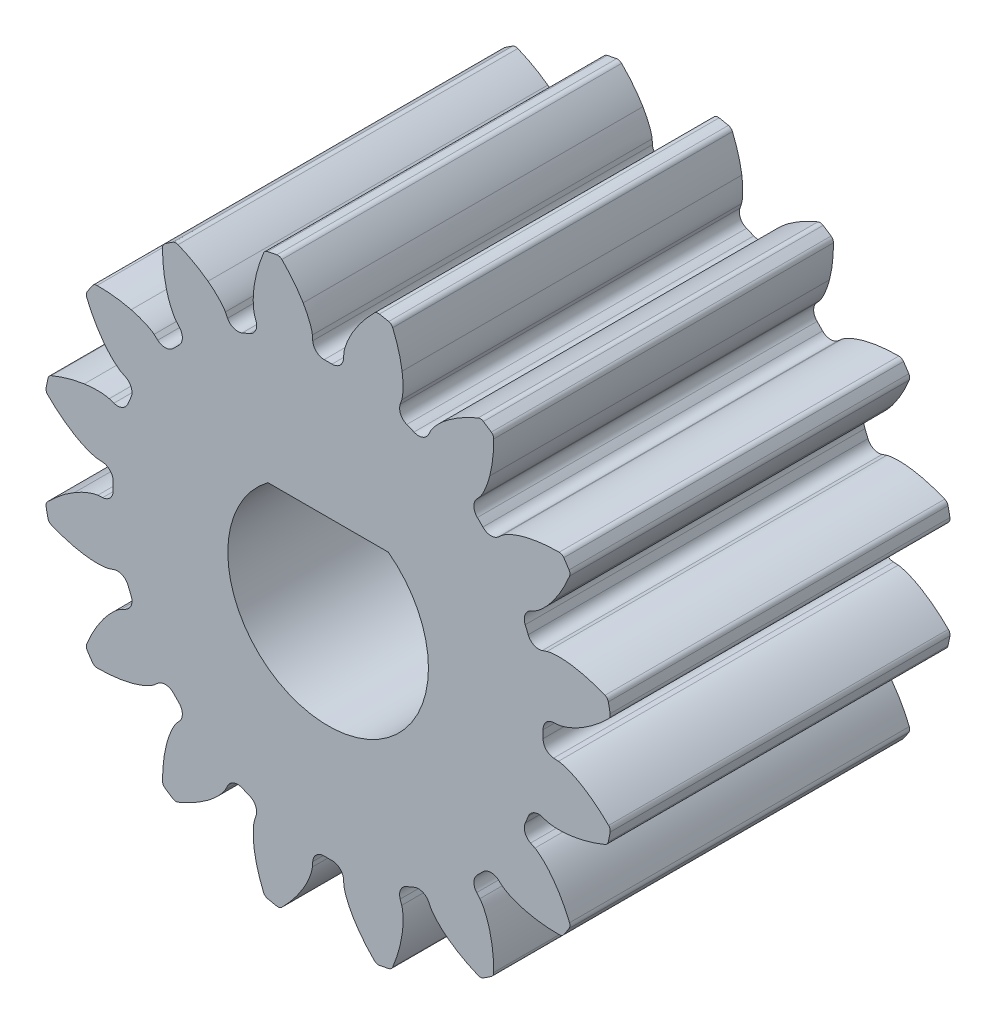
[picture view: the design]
SolidWorks part; units mm, degrees
ref_plane "Front Plane" through (0, 0, 0) normal (0, 0, 1) x (1, 0, 0)
ref_plane "Top Plane" through (0, 0, 0) normal (0, 1, 0) x (1, 0, 0)
ref_plane "Right Plane" through (0, 0, 0) normal (1, 0, 0) x (0, 0, -1)
sketch "Sketch1" plane through (0, 0, 0) normal (0, 0, 1) x (1, 0, 0)
  line L1 (-1.8, 2.4) -> (1.8, 2.4)
  circle A0 centre (0, 0) radius 7.62
  arc A2 (-1.8, 2.4) -> (1.8, 2.4) centre (0, 0) ccw
  dimension "D1" = 15.24
extrude "Boss-Extrude1" add sketch "Sketch1" against normal blind 10.16
sketch "Sketch2" plane through (0, 0, 0) normal (0, 0, 1) x (1, 0, 0)
  line L0 (3.0715, 6.1854) -> (3.0064, 6.0543)
  line L1 (2.1552, 6.4069) -> (2.2019, 6.5456)
  line L2 (0.4706, 6.89) -> (0.4606, 6.7439)
  line L3 (-0.4606, 6.7439) -> (-0.4706, 6.89)
  line L4 (-2.2019, 6.5456) -> (-2.1552, 6.4069)
  line L5 (-3.0064, 6.0543) -> (-3.0715, 6.1854)
  line L6 (-4.5392, 5.2048) -> (-4.443, 5.0944)
  line L7 (-5.0944, 4.443) -> (-5.2048, 4.5392)
  line L8 (-6.1854, 3.0715) -> (-6.0543, 3.0064)
  line L9 (-6.4069, 2.1552) -> (-6.5456, 2.2019)
  line L10 (-6.89, 0.4706) -> (-6.7439, 0.4606)
  line L11 (-6.7439, -0.4606) -> (-6.89, -0.4706)
  line L12 (-6.5456, -2.2019) -> (-6.4069, -2.1552)
  line L13 (-6.0543, -3.0064) -> (-6.1854, -3.0715)
  line L14 (-5.2048, -4.5392) -> (-5.0944, -4.443)
  line L15 (-4.443, -5.0944) -> (-4.5392, -5.2048)
  line L16 (-3.0715, -6.1854) -> (-3.0064, -6.0543)
  line L17 (-2.1552, -6.4069) -> (-2.2019, -6.5456)
  line L18 (-0.4706, -6.89) -> (-0.4606, -6.7439)
  line L19 (0.4606, -6.7439) -> (0.4706, -6.89)
  line L20 (2.2019, -6.5456) -> (2.1552, -6.4069)
  line L21 (3.0064, -6.0543) -> (3.0715, -6.1854)
  line L22 (4.5392, -5.2048) -> (4.443, -5.0944)
  line L23 (5.0944, -4.443) -> (5.2048, -4.5392)
  line L24 (6.1854, -3.0715) -> (6.0543, -3.0064)
  line L25 (6.4069, -2.1552) -> (6.5456, -2.2019)
  line L26 (6.89, -0.4706) -> (6.7439, -0.4606)
  line L27 (6.7439, 0.4606) -> (6.89, 0.4706)
  line L28 (6.5456, 2.2019) -> (6.4069, 2.1552)
  line L29 (6.0543, 3.0064) -> (6.1854, 3.0715)
  line L30 (5.2048, 4.5392) -> (5.0944, 4.443)
  line L31 (4.443, 5.0944) -> (4.5392, 5.2048)
  arc A2 (2.5677, 5.8944) -> (3.0064, 6.0543) centre (2.703, 6.205) ccw
  arc A3 (2.5677, 5.8944) -> (2.3523, 5.9836) centre (0, 0) ccw
  arc A4 (2.1552, 6.4069) -> (2.3523, 5.9836) centre (2.4763, 6.2989) ccw
  arc A8 (0.1165, 6.4283) -> (0.4606, 6.7439) centre (0.1227, 6.767) ccw
  arc A9 (0.1165, 6.4283) -> (-0.1165, 6.4283) centre (0, 0) ccw
  arc A10 (-0.4606, 6.7439) -> (-0.1165, 6.4283) centre (-0.1227, 6.767) ccw
  arc A14 (-2.3523, 5.9836) -> (-2.1552, 6.4069) centre (-2.4763, 6.2989) ccw
  arc A15 (-2.3523, 5.9836) -> (-2.5677, 5.8944) centre (0, 0) ccw
  arc A16 (-3.0064, 6.0543) -> (-2.5677, 5.8944) centre (-2.703, 6.205) ccw
  arc A20 (-4.4631, 4.6279) -> (-4.443, 5.0944) centre (-4.6983, 4.8718) ccw
  arc A21 (-4.4631, 4.6279) -> (-4.6279, 4.4631) centre (0, 0) ccw
  arc A22 (-5.0944, 4.443) -> (-4.6279, 4.4631) centre (-4.8718, 4.6983) ccw
  arc A26 (-5.8944, 2.5677) -> (-6.0543, 3.0064) centre (-6.205, 2.703) ccw
  arc A27 (-5.8944, 2.5677) -> (-5.9836, 2.3523) centre (0, 0) ccw
  arc A28 (-6.4069, 2.1552) -> (-5.9836, 2.3523) centre (-6.2989, 2.4763) ccw
  arc A32 (-6.4283, 0.1165) -> (-6.7439, 0.4606) centre (-6.767, 0.1227) ccw
  arc A33 (-6.4283, 0.1165) -> (-6.4283, -0.1165) centre (0, 0) ccw
  arc A34 (-6.7439, -0.4606) -> (-6.4283, -0.1165) centre (-6.767, -0.1227) ccw
  arc A38 (-5.9836, -2.3523) -> (-6.4069, -2.1552) centre (-6.2989, -2.4763) ccw
  arc A39 (-5.9836, -2.3523) -> (-5.8944, -2.5677) centre (0, 0) ccw
  arc A40 (-6.0543, -3.0064) -> (-5.8944, -2.5677) centre (-6.205, -2.703) ccw
  arc A44 (-4.6279, -4.4631) -> (-5.0944, -4.443) centre (-4.8718, -4.6983) ccw
  arc A45 (-4.6279, -4.4631) -> (-4.4631, -4.6279) centre (0, 0) ccw
  arc A46 (-4.443, -5.0944) -> (-4.4631, -4.6279) centre (-4.6983, -4.8718) ccw
  arc A50 (-2.5677, -5.8944) -> (-3.0064, -6.0543) centre (-2.703, -6.205) ccw
  arc A51 (-2.5677, -5.8944) -> (-2.3523, -5.9836) centre (0, 0) ccw
  arc A52 (-2.1552, -6.4069) -> (-2.3523, -5.9836) centre (-2.4763, -6.2989) ccw
  arc A56 (-0.1165, -6.4283) -> (-0.4606, -6.7439) centre (-0.1227, -6.767) ccw
  arc A57 (-0.1165, -6.4283) -> (0.1165, -6.4283) centre (0, 0) ccw
  arc A58 (0.4606, -6.7439) -> (0.1165, -6.4283) centre (0.1227, -6.767) ccw
  arc A62 (2.3523, -5.9836) -> (2.1552, -6.4069) centre (2.4763, -6.2989) ccw
  arc A63 (2.3523, -5.9836) -> (2.5677, -5.8944) centre (0, 0) ccw
  arc A64 (3.0064, -6.0543) -> (2.5677, -5.8944) centre (2.703, -6.205) ccw
  arc A68 (4.4631, -4.6279) -> (4.443, -5.0944) centre (4.6983, -4.8718) ccw
  arc A69 (4.4631, -4.6279) -> (4.6279, -4.4631) centre (0, 0) ccw
  arc A70 (5.0944, -4.443) -> (4.6279, -4.4631) centre (4.8718, -4.6983) ccw
  arc A74 (5.8944, -2.5677) -> (6.0543, -3.0064) centre (6.205, -2.703) ccw
  arc A75 (5.8944, -2.5677) -> (5.9836, -2.3523) centre (0, 0) ccw
  arc A76 (6.4069, -2.1552) -> (5.9836, -2.3523) centre (6.2989, -2.4763) ccw
  arc A80 (6.4283, -0.1165) -> (6.7439, -0.4606) centre (6.767, -0.1227) ccw
  arc A81 (6.4283, -0.1165) -> (6.4283, 0.1165) centre (0, 0) ccw
  arc A82 (6.7439, 0.4606) -> (6.4283, 0.1165) centre (6.767, 0.1227) ccw
  arc A86 (5.9836, 2.3523) -> (6.4069, 2.1552) centre (6.2989, 2.4763) ccw
  arc A87 (5.9836, 2.3523) -> (5.8944, 2.5677) centre (0, 0) ccw
  arc A88 (6.0543, 3.0064) -> (5.8944, 2.5677) centre (6.205, 2.703) ccw
  arc A92 (4.6279, 4.4631) -> (5.0944, 4.443) centre (4.8718, 4.6983) ccw
  arc A93 (4.6279, 4.4631) -> (4.4631, 4.6279) centre (0, 0) ccw
  arc A94 (4.443, 5.0944) -> (4.4631, 4.6279) centre (4.6983, 4.8718) ccw
  circle A96 centre (0, 0) radius 7.62 construction
  arc A97 (-2.212, 7.2919) -> (-3.592, 6.7202) centre (0, 0) ccw
  arc A98 (-4.8341, 5.8903) -> (-5.8903, 4.8341) centre (0, 0) ccw
  arc A99 (-6.7202, 3.592) -> (-7.2919, 2.212) centre (0, 0) ccw
  arc A100 (-7.5833, 0.7469) -> (-7.5833, -0.7469) centre (0, 0) ccw
  arc A101 (-7.2919, -2.212) -> (-6.7202, -3.592) centre (0, 0) ccw
  arc A102 (-5.8903, -4.8341) -> (-4.8341, -5.8903) centre (0, 0) ccw
  arc A103 (-3.592, -6.7202) -> (-2.212, -7.2919) centre (0, 0) ccw
  arc A104 (-0.7469, -7.5833) -> (0.7469, -7.5833) centre (0, 0) ccw
  arc A105 (2.212, -7.2919) -> (3.592, -6.7202) centre (0, 0) ccw
  arc A106 (4.8341, -5.8903) -> (5.8903, -4.8341) centre (0, 0) ccw
  arc A107 (6.7202, -3.592) -> (7.2919, -2.212) centre (0, 0) ccw
  arc A108 (7.5833, -0.7469) -> (7.5833, 0.7469) centre (0, 0) ccw
  arc A109 (7.2919, 2.212) -> (6.7202, 3.592) centre (0, 0) ccw
  arc A110 (5.8903, 4.8341) -> (4.8341, 5.8903) centre (0, 0) ccw
  arc A111 (3.592, 6.7202) -> (2.212, 7.2919) centre (0, 0) ccw
  arc A112 (0.7469, 7.5833) -> (-0.7469, 7.5833) centre (0, 0) ccw
  spline S0 degree 4 poles (3.592, 6.7202) (3.568, 6.7022) (3.5237, 6.668) (3.469, 6.6239) (3.4054, 6.5688) (3.355, 6.5228) (3.3144, 6.4839) (3.2747, 6.4441) (3.2361, 6.4032) (3.1925, 6.3543) (3.1539, 6.3073) (3.1216, 6.2645) (3.0966, 6.2276) (3.0838, 6.2074) (3.0764, 6.1947) (3.0728, 6.1879) (3.0715, 6.1854) knots 0.498722 0.498722 0.498722 0.498722 0.498722 0.557202 0.60793 0.635296 0.662662 0.690028 0.717395 0.744761 0.772127 0.817627 0.835706 0.849154 0.858861 0.864237 0.864237 0.864237 0.864237 0.864237
  spline S1 degree 4 poles (2.2019, 6.5456) (2.2027, 6.5483) (2.205, 6.5557) (2.2087, 6.5699) (2.214, 6.5932) (2.2224, 6.637) (2.2298, 6.6901) (2.2357, 6.7506) (2.2395, 6.816) (2.2411, 6.8722) (2.2412, 6.9284) (2.24, 6.9846) (2.2369, 7.0528) (2.2308, 7.1367) (2.2234, 7.2066) (2.2162, 7.2622) (2.212, 7.2919) knots 0 0 0 0 0 0.005377 0.015084 0.028532 0.04661 0.092111 0.119476 0.146842 0.174209 0.201575 0.228941 0.256307 0.307035 0.365516 0.365516 0.365516 0.365516 0.365516
  spline S2 degree 4 poles (0.7469, 7.5833) (0.7316, 7.5575) (0.7037, 7.5089) (0.6701, 7.4472) (0.6324, 7.372) (0.6035, 7.3102) (0.5808, 7.2587) (0.5594, 7.2067) (0.5394, 7.1542) (0.5178, 7.0923) (0.5001, 7.0342) (0.4867, 6.9822) (0.4776, 6.9386) (0.4736, 6.915) (0.4716, 6.9005) (0.4709, 6.8928) (0.4706, 6.89) knots 0.498722 0.498722 0.498722 0.498722 0.498722 0.557202 0.60793 0.635296 0.662662 0.690028 0.717395 0.744761 0.772127 0.817627 0.835706 0.849154 0.858861 0.864237 0.864237 0.864237 0.864237 0.864237
  spline S3 degree 4 poles (-0.4706, 6.89) (-0.4709, 6.8928) (-0.4716, 6.9005) (-0.4736, 6.915) (-0.4776, 6.9386) (-0.4867, 6.9822) (-0.5001, 7.0342) (-0.5178, 7.0923) (-0.5394, 7.1542) (-0.5594, 7.2067) (-0.5808, 7.2587) (-0.6035, 7.3102) (-0.6324, 7.372) (-0.6701, 7.4472) (-0.7037, 7.5089) (-0.7316, 7.5575) (-0.7469, 7.5833) knots 0 0 0 0 0 0.005377 0.015084 0.028532 0.04661 0.092111 0.119476 0.146842 0.174209 0.201575 0.228941 0.256307 0.307035 0.365516 0.365516 0.365516 0.365516 0.365516
  spline S4 degree 4 poles (-2.212, 7.2919) (-2.2162, 7.2622) (-2.2234, 7.2066) (-2.2308, 7.1367) (-2.2369, 7.0528) (-2.24, 6.9846) (-2.2412, 6.9284) (-2.2411, 6.8722) (-2.2395, 6.816) (-2.2357, 6.7506) (-2.2298, 6.6901) (-2.2224, 6.637) (-2.214, 6.5932) (-2.2087, 6.5699) (-2.205, 6.5557) (-2.2027, 6.5483) (-2.2019, 6.5456) knots 0.498722 0.498722 0.498722 0.498722 0.498722 0.557202 0.60793 0.635296 0.662662 0.690028 0.717395 0.744761 0.772127 0.817627 0.835706 0.849154 0.858861 0.864237 0.864237 0.864237 0.864237 0.864237
  spline S5 degree 4 poles (-3.0715, 6.1854) (-3.0728, 6.1879) (-3.0764, 6.1947) (-3.0838, 6.2074) (-3.0966, 6.2276) (-3.1216, 6.2645) (-3.1539, 6.3073) (-3.1925, 6.3543) (-3.2361, 6.4032) (-3.2747, 6.4441) (-3.3144, 6.4839) (-3.355, 6.5228) (-3.4054, 6.5688) (-3.469, 6.6239) (-3.5237, 6.668) (-3.568, 6.7022) (-3.592, 6.7202) knots 0 0 0 0 0 0.005377 0.015084 0.028532 0.04661 0.092111 0.119476 0.146842 0.174209 0.201575 0.228941 0.256307 0.307035 0.365516 0.365516 0.365516 0.365516 0.365516
  spline S6 degree 4 poles (-4.8341, 5.8903) (-4.8266, 5.8613) (-4.812, 5.8072) (-4.7921, 5.7398) (-4.7656, 5.6599) (-4.7424, 5.5958) (-4.722, 5.5434) (-4.7004, 5.4915) (-4.6774, 5.4402) (-4.6489, 5.3812) (-4.6203, 5.3275) (-4.5931, 5.2813) (-4.5686, 5.2441) (-4.5547, 5.2245) (-4.5459, 5.2129) (-4.541, 5.2069) (-4.5392, 5.2048) knots 0.498722 0.498722 0.498722 0.498722 0.498722 0.557202 0.60793 0.635296 0.662662 0.690028 0.717395 0.744761 0.772127 0.817627 0.835706 0.849154 0.858861 0.864237 0.864237 0.864237 0.864237 0.864237
  spline S7 degree 4 poles (-5.2048, 4.5392) (-5.2069, 4.541) (-5.2129, 4.5459) (-5.2245, 4.5547) (-5.2441, 4.5686) (-5.2813, 4.5931) (-5.3275, 4.6203) (-5.3812, 4.6489) (-5.4402, 4.6774) (-5.4915, 4.7004) (-5.5434, 4.722) (-5.5958, 4.7424) (-5.6599, 4.7656) (-5.7398, 4.7921) (-5.8072, 4.812) (-5.8613, 4.8266) (-5.8903, 4.8341) knots 0 0 0 0 0 0.005377 0.015084 0.028532 0.04661 0.092111 0.119476 0.146842 0.174209 0.201575 0.228941 0.256307 0.307035 0.365516 0.365516 0.365516 0.365516 0.365516
  spline S8 degree 4 poles (-6.7202, 3.592) (-6.7022, 3.568) (-6.668, 3.5237) (-6.6239, 3.469) (-6.5688, 3.4054) (-6.5228, 3.355) (-6.4839, 3.3144) (-6.4441, 3.2747) (-6.4032, 3.2361) (-6.3543, 3.1925) (-6.3073, 3.1539) (-6.2645, 3.1216) (-6.2276, 3.0966) (-6.2074, 3.0838) (-6.1947, 3.0764) (-6.1879, 3.0728) (-6.1854, 3.0715) knots 0.498722 0.498722 0.498722 0.498722 0.498722 0.557202 0.60793 0.635296 0.662662 0.690028 0.717395 0.744761 0.772127 0.817627 0.835706 0.849154 0.858861 0.864237 0.864237 0.864237 0.864237 0.864237
  spline S9 degree 4 poles (-6.5456, 2.2019) (-6.5483, 2.2027) (-6.5557, 2.205) (-6.5699, 2.2087) (-6.5932, 2.214) (-6.637, 2.2224) (-6.6901, 2.2298) (-6.7506, 2.2357) (-6.816, 2.2395) (-6.8722, 2.2411) (-6.9284, 2.2412) (-6.9846, 2.24) (-7.0528, 2.2369) (-7.1367, 2.2308) (-7.2066, 2.2234) (-7.2622, 2.2162) (-7.2919, 2.212) knots 0 0 0 0 0 0.005377 0.015084 0.028532 0.04661 0.092111 0.119476 0.146842 0.174209 0.201575 0.228941 0.256307 0.307035 0.365516 0.365516 0.365516 0.365516 0.365516
  spline S10 degree 4 poles (-7.5833, 0.7469) (-7.5575, 0.7316) (-7.5089, 0.7037) (-7.4472, 0.6701) (-7.372, 0.6324) (-7.3102, 0.6035) (-7.2587, 0.5808) (-7.2067, 0.5594) (-7.1542, 0.5394) (-7.0923, 0.5178) (-7.0342, 0.5001) (-6.9822, 0.4867) (-6.9386, 0.4776) (-6.915, 0.4736) (-6.9005, 0.4716) (-6.8928, 0.4709) (-6.89, 0.4706) knots 0.498722 0.498722 0.498722 0.498722 0.498722 0.557202 0.60793 0.635296 0.662662 0.690028 0.717395 0.744761 0.772127 0.817627 0.835706 0.849154 0.858861 0.864237 0.864237 0.864237 0.864237 0.864237
  spline S11 degree 4 poles (-6.89, -0.4706) (-6.8928, -0.4709) (-6.9005, -0.4716) (-6.915, -0.4736) (-6.9386, -0.4776) (-6.9822, -0.4867) (-7.0342, -0.5001) (-7.0923, -0.5178) (-7.1542, -0.5394) (-7.2067, -0.5594) (-7.2587, -0.5808) (-7.3102, -0.6035) (-7.372, -0.6324) (-7.4472, -0.6701) (-7.5089, -0.7037) (-7.5575, -0.7316) (-7.5833, -0.7469) knots 0 0 0 0 0 0.005377 0.015084 0.028532 0.04661 0.092111 0.119476 0.146842 0.174209 0.201575 0.228941 0.256307 0.307035 0.365516 0.365516 0.365516 0.365516 0.365516
  spline S12 degree 4 poles (-7.2919, -2.212) (-7.2622, -2.2162) (-7.2066, -2.2234) (-7.1367, -2.2308) (-7.0528, -2.2369) (-6.9846, -2.24) (-6.9284, -2.2412) (-6.8722, -2.2411) (-6.816, -2.2395) (-6.7506, -2.2357) (-6.6901, -2.2298) (-6.637, -2.2224) (-6.5932, -2.214) (-6.5699, -2.2087) (-6.5557, -2.205) (-6.5483, -2.2027) (-6.5456, -2.2019) knots 0.498722 0.498722 0.498722 0.498722 0.498722 0.557202 0.60793 0.635296 0.662662 0.690028 0.717395 0.744761 0.772127 0.817627 0.835706 0.849154 0.858861 0.864237 0.864237 0.864237 0.864237 0.864237
  spline S13 degree 4 poles (-6.1854, -3.0715) (-6.1879, -3.0728) (-6.1947, -3.0764) (-6.2074, -3.0838) (-6.2276, -3.0966) (-6.2645, -3.1216) (-6.3073, -3.1539) (-6.3543, -3.1925) (-6.4032, -3.2361) (-6.4441, -3.2747) (-6.4839, -3.3144) (-6.5228, -3.355) (-6.5688, -3.4054) (-6.6239, -3.469) (-6.668, -3.5237) (-6.7022, -3.568) (-6.7202, -3.592) knots 0 0 0 0 0 0.005377 0.015084 0.028532 0.04661 0.092111 0.119476 0.146842 0.174209 0.201575 0.228941 0.256307 0.307035 0.365516 0.365516 0.365516 0.365516 0.365516
  spline S14 degree 4 poles (-5.8903, -4.8341) (-5.8613, -4.8266) (-5.8072, -4.812) (-5.7398, -4.7921) (-5.6599, -4.7656) (-5.5958, -4.7424) (-5.5434, -4.722) (-5.4915, -4.7004) (-5.4402, -4.6774) (-5.3812, -4.6489) (-5.3275, -4.6203) (-5.2813, -4.5931) (-5.2441, -4.5686) (-5.2245, -4.5547) (-5.2129, -4.5459) (-5.2069, -4.541) (-5.2048, -4.5392) knots 0.498722 0.498722 0.498722 0.498722 0.498722 0.557202 0.60793 0.635296 0.662662 0.690028 0.717395 0.744761 0.772127 0.817627 0.835706 0.849154 0.858861 0.864237 0.864237 0.864237 0.864237 0.864237
  spline S15 degree 4 poles (-4.5392, -5.2048) (-4.541, -5.2069) (-4.5459, -5.2129) (-4.5547, -5.2245) (-4.5686, -5.2441) (-4.5931, -5.2813) (-4.6203, -5.3275) (-4.6489, -5.3812) (-4.6774, -5.4402) (-4.7004, -5.4915) (-4.722, -5.5434) (-4.7424, -5.5958) (-4.7656, -5.6599) (-4.7921, -5.7398) (-4.812, -5.8072) (-4.8266, -5.8613) (-4.8341, -5.8903) knots 0 0 0 0 0 0.005377 0.015084 0.028532 0.04661 0.092111 0.119476 0.146842 0.174209 0.201575 0.228941 0.256307 0.307035 0.365516 0.365516 0.365516 0.365516 0.365516
  spline S16 degree 4 poles (-3.592, -6.7202) (-3.568, -6.7022) (-3.5237, -6.668) (-3.469, -6.6239) (-3.4054, -6.5688) (-3.355, -6.5228) (-3.3144, -6.4839) (-3.2747, -6.4441) (-3.2361, -6.4032) (-3.1925, -6.3543) (-3.1539, -6.3073) (-3.1216, -6.2645) (-3.0966, -6.2276) (-3.0838, -6.2074) (-3.0764, -6.1947) (-3.0728, -6.1879) (-3.0715, -6.1854) knots 0.498722 0.498722 0.498722 0.498722 0.498722 0.557202 0.60793 0.635296 0.662662 0.690028 0.717395 0.744761 0.772127 0.817627 0.835706 0.849154 0.858861 0.864237 0.864237 0.864237 0.864237 0.864237
  spline S17 degree 4 poles (-2.2019, -6.5456) (-2.2027, -6.5483) (-2.205, -6.5557) (-2.2087, -6.5699) (-2.214, -6.5932) (-2.2224, -6.637) (-2.2298, -6.6901) (-2.2357, -6.7506) (-2.2395, -6.816) (-2.2411, -6.8722) (-2.2412, -6.9284) (-2.24, -6.9846) (-2.2369, -7.0528) (-2.2308, -7.1367) (-2.2234, -7.2066) (-2.2162, -7.2622) (-2.212, -7.2919) knots 0 0 0 0 0 0.005377 0.015084 0.028532 0.04661 0.092111 0.119476 0.146842 0.174209 0.201575 0.228941 0.256307 0.307035 0.365516 0.365516 0.365516 0.365516 0.365516
  spline S18 degree 4 poles (-0.7469, -7.5833) (-0.7316, -7.5575) (-0.7037, -7.5089) (-0.6701, -7.4472) (-0.6324, -7.372) (-0.6035, -7.3102) (-0.5808, -7.2587) (-0.5594, -7.2067) (-0.5394, -7.1542) (-0.5178, -7.0923) (-0.5001, -7.0342) (-0.4867, -6.9822) (-0.4776, -6.9386) (-0.4736, -6.915) (-0.4716, -6.9005) (-0.4709, -6.8928) (-0.4706, -6.89) knots 0.498722 0.498722 0.498722 0.498722 0.498722 0.557202 0.60793 0.635296 0.662662 0.690028 0.717395 0.744761 0.772127 0.817627 0.835706 0.849154 0.858861 0.864237 0.864237 0.864237 0.864237 0.864237
  spline S19 degree 4 poles (0.4706, -6.89) (0.4709, -6.8928) (0.4716, -6.9005) (0.4736, -6.915) (0.4776, -6.9386) (0.4867, -6.9822) (0.5001, -7.0342) (0.5178, -7.0923) (0.5394, -7.1542) (0.5594, -7.2067) (0.5808, -7.2587) (0.6035, -7.3102) (0.6324, -7.372) (0.6701, -7.4472) (0.7037, -7.5089) (0.7316, -7.5575) (0.7469, -7.5833) knots 0 0 0 0 0 0.005377 0.015084 0.028532 0.04661 0.092111 0.119476 0.146842 0.174209 0.201575 0.228941 0.256307 0.307035 0.365516 0.365516 0.365516 0.365516 0.365516
  spline S20 degree 4 poles (2.212, -7.2919) (2.2162, -7.2622) (2.2234, -7.2066) (2.2308, -7.1367) (2.2369, -7.0528) (2.24, -6.9846) (2.2412, -6.9284) (2.2411, -6.8722) (2.2395, -6.816) (2.2357, -6.7506) (2.2298, -6.6901) (2.2224, -6.637) (2.214, -6.5932) (2.2087, -6.5699) (2.205, -6.5557) (2.2027, -6.5483) (2.2019, -6.5456) knots 0.498722 0.498722 0.498722 0.498722 0.498722 0.557202 0.60793 0.635296 0.662662 0.690028 0.717395 0.744761 0.772127 0.817627 0.835706 0.849154 0.858861 0.864237 0.864237 0.864237 0.864237 0.864237
  spline S21 degree 4 poles (3.0715, -6.1854) (3.0728, -6.1879) (3.0764, -6.1947) (3.0838, -6.2074) (3.0966, -6.2276) (3.1216, -6.2645) (3.1539, -6.3073) (3.1925, -6.3543) (3.2361, -6.4032) (3.2747, -6.4441) (3.3144, -6.4839) (3.355, -6.5228) (3.4054, -6.5688) (3.469, -6.6239) (3.5237, -6.668) (3.568, -6.7022) (3.592, -6.7202) knots 0 0 0 0 0 0.005377 0.015084 0.028532 0.04661 0.092111 0.119476 0.146842 0.174209 0.201575 0.228941 0.256307 0.307035 0.365516 0.365516 0.365516 0.365516 0.365516
  spline S22 degree 4 poles (4.8341, -5.8903) (4.8266, -5.8613) (4.812, -5.8072) (4.7921, -5.7398) (4.7656, -5.6599) (4.7424, -5.5958) (4.722, -5.5434) (4.7004, -5.4915) (4.6774, -5.4402) (4.6489, -5.3812) (4.6203, -5.3275) (4.5931, -5.2813) (4.5686, -5.2441) (4.5547, -5.2245) (4.5459, -5.2129) (4.541, -5.2069) (4.5392, -5.2048) knots 0.498722 0.498722 0.498722 0.498722 0.498722 0.557202 0.60793 0.635296 0.662662 0.690028 0.717395 0.744761 0.772127 0.817627 0.835706 0.849154 0.858861 0.864237 0.864237 0.864237 0.864237 0.864237
  spline S23 degree 4 poles (5.2048, -4.5392) (5.2069, -4.541) (5.2129, -4.5459) (5.2245, -4.5547) (5.2441, -4.5686) (5.2813, -4.5931) (5.3275, -4.6203) (5.3812, -4.6489) (5.4402, -4.6774) (5.4915, -4.7004) (5.5434, -4.722) (5.5958, -4.7424) (5.6599, -4.7656) (5.7398, -4.7921) (5.8072, -4.812) (5.8613, -4.8266) (5.8903, -4.8341) knots 0 0 0 0 0 0.005377 0.015084 0.028532 0.04661 0.092111 0.119476 0.146842 0.174209 0.201575 0.228941 0.256307 0.307035 0.365516 0.365516 0.365516 0.365516 0.365516
  spline S24 degree 4 poles (6.7202, -3.592) (6.7022, -3.568) (6.668, -3.5237) (6.6239, -3.469) (6.5688, -3.4054) (6.5228, -3.355) (6.4839, -3.3144) (6.4441, -3.2747) (6.4032, -3.2361) (6.3543, -3.1925) (6.3073, -3.1539) (6.2645, -3.1216) (6.2276, -3.0966) (6.2074, -3.0838) (6.1947, -3.0764) (6.1879, -3.0728) (6.1854, -3.0715) knots 0.498722 0.498722 0.498722 0.498722 0.498722 0.557202 0.60793 0.635296 0.662662 0.690028 0.717395 0.744761 0.772127 0.817627 0.835706 0.849154 0.858861 0.864237 0.864237 0.864237 0.864237 0.864237
  spline S25 degree 4 poles (6.5456, -2.2019) (6.5483, -2.2027) (6.5557, -2.205) (6.5699, -2.2087) (6.5932, -2.214) (6.637, -2.2224) (6.6901, -2.2298) (6.7506, -2.2357) (6.816, -2.2395) (6.8722, -2.2411) (6.9284, -2.2412) (6.9846, -2.24) (7.0528, -2.2369) (7.1367, -2.2308) (7.2066, -2.2234) (7.2622, -2.2162) (7.2919, -2.212) knots 0 0 0 0 0 0.005377 0.015084 0.028532 0.04661 0.092111 0.119476 0.146842 0.174209 0.201575 0.228941 0.256307 0.307035 0.365516 0.365516 0.365516 0.365516 0.365516
  spline S26 degree 4 poles (7.5833, -0.7469) (7.5575, -0.7316) (7.5089, -0.7037) (7.4472, -0.6701) (7.372, -0.6324) (7.3102, -0.6035) (7.2587, -0.5808) (7.2067, -0.5594) (7.1542, -0.5394) (7.0923, -0.5178) (7.0342, -0.5001) (6.9822, -0.4867) (6.9386, -0.4776) (6.915, -0.4736) (6.9005, -0.4716) (6.8928, -0.4709) (6.89, -0.4706) knots 0.498722 0.498722 0.498722 0.498722 0.498722 0.557202 0.60793 0.635296 0.662662 0.690028 0.717395 0.744761 0.772127 0.817627 0.835706 0.849154 0.858861 0.864237 0.864237 0.864237 0.864237 0.864237
  spline S27 degree 4 poles (6.89, 0.4706) (6.8928, 0.4709) (6.9005, 0.4716) (6.915, 0.4736) (6.9386, 0.4776) (6.9822, 0.4867) (7.0342, 0.5001) (7.0923, 0.5178) (7.1542, 0.5394) (7.2067, 0.5594) (7.2587, 0.5808) (7.3102, 0.6035) (7.372, 0.6324) (7.4472, 0.6701) (7.5089, 0.7037) (7.5575, 0.7316) (7.5833, 0.7469) knots 0 0 0 0 0 0.005377 0.015084 0.028532 0.04661 0.092111 0.119476 0.146842 0.174209 0.201575 0.228941 0.256307 0.307035 0.365516 0.365516 0.365516 0.365516 0.365516
  spline S28 degree 4 poles (7.2919, 2.212) (7.2622, 2.2162) (7.2066, 2.2234) (7.1367, 2.2308) (7.0528, 2.2369) (6.9846, 2.24) (6.9284, 2.2412) (6.8722, 2.2411) (6.816, 2.2395) (6.7506, 2.2357) (6.6901, 2.2298) (6.637, 2.2224) (6.5932, 2.214) (6.5699, 2.2087) (6.5557, 2.205) (6.5483, 2.2027) (6.5456, 2.2019) knots 0.498722 0.498722 0.498722 0.498722 0.498722 0.557202 0.60793 0.635296 0.662662 0.690028 0.717395 0.744761 0.772127 0.817627 0.835706 0.849154 0.858861 0.864237 0.864237 0.864237 0.864237 0.864237
  spline S29 degree 4 poles (6.1854, 3.0715) (6.1879, 3.0728) (6.1947, 3.0764) (6.2074, 3.0838) (6.2276, 3.0966) (6.2645, 3.1216) (6.3073, 3.1539) (6.3543, 3.1925) (6.4032, 3.2361) (6.4441, 3.2747) (6.4839, 3.3144) (6.5228, 3.355) (6.5688, 3.4054) (6.6239, 3.469) (6.668, 3.5237) (6.7022, 3.568) (6.7202, 3.592) knots 0 0 0 0 0 0.005377 0.015084 0.028532 0.04661 0.092111 0.119476 0.146842 0.174209 0.201575 0.228941 0.256307 0.307035 0.365516 0.365516 0.365516 0.365516 0.365516
  spline S30 degree 4 poles (5.8903, 4.8341) (5.8613, 4.8266) (5.8072, 4.812) (5.7398, 4.7921) (5.6599, 4.7656) (5.5958, 4.7424) (5.5434, 4.722) (5.4915, 4.7004) (5.4402, 4.6774) (5.3812, 4.6489) (5.3275, 4.6203) (5.2813, 4.5931) (5.2441, 4.5686) (5.2245, 4.5547) (5.2129, 4.5459) (5.2069, 4.541) (5.2048, 4.5392) knots 0.498722 0.498722 0.498722 0.498722 0.498722 0.557202 0.60793 0.635296 0.662662 0.690028 0.717395 0.744761 0.772127 0.817627 0.835706 0.849154 0.858861 0.864237 0.864237 0.864237 0.864237 0.864237
  spline S31 degree 4 poles (4.5392, 5.2048) (4.541, 5.2069) (4.5459, 5.2129) (4.5547, 5.2245) (4.5686, 5.2441) (4.5931, 5.2813) (4.6203, 5.3275) (4.6489, 5.3812) (4.6774, 5.4402) (4.7004, 5.4915) (4.722, 5.5434) (4.7424, 5.5958) (4.7656, 5.6599) (4.7921, 5.7398) (4.812, 5.8072) (4.8266, 5.8613) (4.8341, 5.8903) knots 0 0 0 0 0 0.005377 0.015084 0.028532 0.04661 0.092111 0.119476 0.146842 0.174209 0.201575 0.228941 0.256307 0.307035 0.365516 0.365516 0.365516 0.365516 0.365516
extrude "Cut-Extrude1" cut sketch "Sketch2" against normal up to surface (10.16 mm away)
sketch "Sketch3" plane through (0, 0, 0) normal (0, 0, 1) x (1, 0, 0)
  line L0 (3.0715, 6.1854) -> (3.0064, 6.0543)
  line L1 (2.1552, 6.4069) -> (2.2019, 6.5456)
  line L2 (0.4706, 6.89) -> (0.4606, 6.7439)
  line L3 (-0.4606, 6.7439) -> (-0.4706, 6.89)
  line L4 (-2.2019, 6.5456) -> (-2.1552, 6.4069)
  line L5 (-3.0064, 6.0543) -> (-3.0715, 6.1854)
  line L6 (-4.5392, 5.2048) -> (-4.443, 5.0944)
  line L7 (-5.0944, 4.443) -> (-5.2048, 4.5392)
  line L8 (-6.1854, 3.0715) -> (-6.0543, 3.0064)
  line L9 (-6.4069, 2.1552) -> (-6.5456, 2.2019)
  line L10 (-6.89, 0.4706) -> (-6.7439, 0.4606)
  line L11 (-6.7439, -0.4606) -> (-6.89, -0.4706)
  line L12 (-6.5456, -2.2019) -> (-6.4069, -2.1552)
  line L13 (-6.0543, -3.0064) -> (-6.1854, -3.0715)
  line L14 (-5.2048, -4.5392) -> (-5.0944, -4.443)
  line L15 (-4.443, -5.0944) -> (-4.5392, -5.2048)
  line L16 (-3.0715, -6.1854) -> (-3.0064, -6.0543)
  line L17 (-2.1552, -6.4069) -> (-2.2019, -6.5456)
  line L18 (-0.4706, -6.89) -> (-0.4606, -6.7439)
  line L19 (0.4606, -6.7439) -> (0.4706, -6.89)
  line L20 (2.2019, -6.5456) -> (2.1552, -6.4069)
  line L21 (3.0064, -6.0543) -> (3.0715, -6.1854)
  line L22 (4.5392, -5.2048) -> (4.443, -5.0944)
  line L23 (5.0944, -4.443) -> (5.2048, -4.5392)
  line L24 (6.1854, -3.0715) -> (6.0543, -3.0064)
  line L25 (6.4069, -2.1552) -> (6.5456, -2.2019)
  line L26 (6.89, -0.4706) -> (6.7439, -0.4606)
  line L27 (6.7439, 0.4606) -> (6.89, 0.4706)
  line L28 (6.5456, 2.2019) -> (6.4069, 2.1552)
  line L29 (6.0543, 3.0064) -> (6.1854, 3.0715)
  line L30 (5.2048, 4.5392) -> (5.0944, 4.443)
  line L31 (4.443, 5.0944) -> (4.5392, 5.2048)
  line L32 (1.8, 2.4) -> (-1.8, 2.4) construction
  line L33 (1.8, 2.4) -> (-1.8, 2.4)
  arc A0 (4.88, 7.0479) -> (4.6439, 7.2057) centre (0, 0) ccw
  arc A1 (4.6439, 7.2057) -> (4.4875, 7.2198) centre (4.5522, 7.0633) ccw
  arc A2 (2.5677, 5.8944) -> (3.0064, 6.0543) centre (2.703, 6.205) ccw
  arc A3 (2.5677, 5.8944) -> (2.3523, 5.9836) centre (0, 0) ccw
  arc A4 (2.1552, 6.4069) -> (2.3523, 5.9836) centre (2.4763, 6.2989) ccw
  arc A5 (1.9321, 8.2783) -> (1.8114, 8.3789) centre (1.7756, 8.2134) ccw
  arc A6 (1.8114, 8.3789) -> (1.533, 8.4343) centre (0, 0) ccw
  arc A7 (1.533, 8.4343) -> (1.383, 8.3875) centre (1.5027, 8.2677) ccw
  arc A8 (0.1165, 6.4283) -> (0.4606, 6.7439) centre (0.1227, 6.767) ccw
  arc A9 (0.1165, 6.4283) -> (-0.1165, 6.4283) centre (0, 0) ccw
  arc A10 (-0.4606, 6.7439) -> (-0.1165, 6.4283) centre (-0.1227, 6.767) ccw
  arc A11 (-1.383, 8.3875) -> (-1.533, 8.4343) centre (-1.5027, 8.2677) ccw
  arc A12 (-1.533, 8.4343) -> (-1.8114, 8.3789) centre (0, 0) ccw
  arc A13 (-1.8114, 8.3789) -> (-1.9321, 8.2783) centre (-1.7756, 8.2134) ccw
  arc A14 (-2.3523, 5.9836) -> (-2.1552, 6.4069) centre (-2.4763, 6.2989) ccw
  arc A15 (-2.3523, 5.9836) -> (-2.5677, 5.8944) centre (0, 0) ccw
  arc A16 (-3.0064, 6.0543) -> (-2.5677, 5.8944) centre (-2.703, 6.205) ccw
  arc A17 (-4.4875, 7.2198) -> (-4.6439, 7.2057) centre (-4.5522, 7.0633) ccw
  arc A18 (-4.6439, 7.2057) -> (-4.88, 7.0479) centre (0, 0) ccw
  arc A19 (-4.88, 7.0479) -> (-4.953, 6.9088) centre (-4.7836, 6.9087) ccw
  arc A20 (-4.4631, 4.6279) -> (-4.443, 5.0944) centre (-4.6983, 4.8718) ccw
  arc A21 (-4.4631, 4.6279) -> (-4.6279, 4.4631) centre (0, 0) ccw
  arc A22 (-5.0944, 4.443) -> (-4.6279, 4.4631) centre (-4.8718, 4.6983) ccw
  arc A23 (-6.9088, 4.953) -> (-7.0479, 4.88) centre (-6.9087, 4.7836) ccw
  arc A24 (-7.0479, 4.88) -> (-7.2057, 4.6439) centre (0, 0) ccw
  arc A25 (-7.2057, 4.6439) -> (-7.2198, 4.4875) centre (-7.0633, 4.5522) ccw
  arc A26 (-5.8944, 2.5677) -> (-6.0543, 3.0064) centre (-6.205, 2.703) ccw
  arc A27 (-5.8944, 2.5677) -> (-5.9836, 2.3523) centre (0, 0) ccw
  arc A28 (-6.4069, 2.1552) -> (-5.9836, 2.3523) centre (-6.2989, 2.4763) ccw
  arc A29 (-8.2783, 1.9321) -> (-8.3789, 1.8114) centre (-8.2134, 1.7756) ccw
  arc A30 (-8.3789, 1.8114) -> (-8.4343, 1.533) centre (0, 0) ccw
  arc A31 (-8.4343, 1.533) -> (-8.3875, 1.383) centre (-8.2677, 1.5027) ccw
  arc A32 (-6.4283, 0.1165) -> (-6.7439, 0.4606) centre (-6.767, 0.1227) ccw
  arc A33 (-6.4283, 0.1165) -> (-6.4283, -0.1165) centre (0, 0) ccw
  arc A34 (-6.7439, -0.4606) -> (-6.4283, -0.1165) centre (-6.767, -0.1227) ccw
  arc A35 (-8.3875, -1.383) -> (-8.4343, -1.533) centre (-8.2677, -1.5027) ccw
  arc A36 (-8.4343, -1.533) -> (-8.3789, -1.8114) centre (0, 0) ccw
  arc A37 (-8.3789, -1.8114) -> (-8.2783, -1.9321) centre (-8.2134, -1.7756) ccw
  arc A38 (-5.9836, -2.3523) -> (-6.4069, -2.1552) centre (-6.2989, -2.4763) ccw
  arc A39 (-5.9836, -2.3523) -> (-5.8944, -2.5677) centre (0, 0) ccw
  arc A40 (-6.0543, -3.0064) -> (-5.8944, -2.5677) centre (-6.205, -2.703) ccw
  arc A41 (-7.2198, -4.4875) -> (-7.2057, -4.6439) centre (-7.0633, -4.5522) ccw
  arc A42 (-7.2057, -4.6439) -> (-7.0479, -4.88) centre (0, 0) ccw
  arc A43 (-7.0479, -4.88) -> (-6.9088, -4.953) centre (-6.9087, -4.7836) ccw
  arc A44 (-4.6279, -4.4631) -> (-5.0944, -4.443) centre (-4.8718, -4.6983) ccw
  arc A45 (-4.6279, -4.4631) -> (-4.4631, -4.6279) centre (0, 0) ccw
  arc A46 (-4.443, -5.0944) -> (-4.4631, -4.6279) centre (-4.6983, -4.8718) ccw
  arc A47 (-4.953, -6.9088) -> (-4.88, -7.0479) centre (-4.7836, -6.9087) ccw
  arc A48 (-4.88, -7.0479) -> (-4.6439, -7.2057) centre (0, 0) ccw
  arc A49 (-4.6439, -7.2057) -> (-4.4875, -7.2198) centre (-4.5522, -7.0633) ccw
  arc A50 (-2.5677, -5.8944) -> (-3.0064, -6.0543) centre (-2.703, -6.205) ccw
  arc A51 (-2.5677, -5.8944) -> (-2.3523, -5.9836) centre (0, 0) ccw
  arc A52 (-2.1552, -6.4069) -> (-2.3523, -5.9836) centre (-2.4763, -6.2989) ccw
  arc A53 (-1.9321, -8.2783) -> (-1.8114, -8.3789) centre (-1.7756, -8.2134) ccw
  arc A54 (-1.8114, -8.3789) -> (-1.533, -8.4343) centre (0, 0) ccw
  arc A55 (-1.533, -8.4343) -> (-1.383, -8.3875) centre (-1.5027, -8.2677) ccw
  arc A56 (-0.1165, -6.4283) -> (-0.4606, -6.7439) centre (-0.1227, -6.767) ccw
  arc A57 (-0.1165, -6.4283) -> (0.1165, -6.4283) centre (0, 0) ccw
  arc A58 (0.4606, -6.7439) -> (0.1165, -6.4283) centre (0.1227, -6.767) ccw
  arc A59 (1.383, -8.3875) -> (1.533, -8.4343) centre (1.5027, -8.2677) ccw
  arc A60 (1.533, -8.4343) -> (1.8114, -8.3789) centre (0, 0) ccw
  arc A61 (1.8114, -8.3789) -> (1.9321, -8.2783) centre (1.7756, -8.2134) ccw
  arc A62 (2.3523, -5.9836) -> (2.1552, -6.4069) centre (2.4763, -6.2989) ccw
  arc A63 (2.3523, -5.9836) -> (2.5677, -5.8944) centre (0, 0) ccw
  arc A64 (3.0064, -6.0543) -> (2.5677, -5.8944) centre (2.703, -6.205) ccw
  arc A65 (4.4875, -7.2198) -> (4.6439, -7.2057) centre (4.5522, -7.0633) ccw
  arc A66 (4.6439, -7.2057) -> (4.88, -7.0479) centre (0, 0) ccw
  arc A67 (4.88, -7.0479) -> (4.953, -6.9088) centre (4.7836, -6.9087) ccw
  arc A68 (4.4631, -4.6279) -> (4.443, -5.0944) centre (4.6983, -4.8718) ccw
  arc A69 (4.4631, -4.6279) -> (4.6279, -4.4631) centre (0, 0) ccw
  arc A70 (5.0944, -4.443) -> (4.6279, -4.4631) centre (4.8718, -4.6983) ccw
  arc A71 (6.9088, -4.953) -> (7.0479, -4.88) centre (6.9087, -4.7836) ccw
  arc A72 (7.0479, -4.88) -> (7.2057, -4.6439) centre (0, 0) ccw
  arc A73 (7.2057, -4.6439) -> (7.2198, -4.4875) centre (7.0633, -4.5522) ccw
  arc A74 (5.8944, -2.5677) -> (6.0543, -3.0064) centre (6.205, -2.703) ccw
  arc A75 (5.8944, -2.5677) -> (5.9836, -2.3523) centre (0, 0) ccw
  arc A76 (6.4069, -2.1552) -> (5.9836, -2.3523) centre (6.2989, -2.4763) ccw
  arc A77 (8.2783, -1.9321) -> (8.3789, -1.8114) centre (8.2134, -1.7756) ccw
  arc A78 (8.3789, -1.8114) -> (8.4343, -1.533) centre (0, 0) ccw
  arc A79 (8.4343, -1.533) -> (8.3875, -1.383) centre (8.2677, -1.5027) ccw
  arc A80 (6.4283, -0.1165) -> (6.7439, -0.4606) centre (6.767, -0.1227) ccw
  arc A81 (6.4283, -0.1165) -> (6.4283, 0.1165) centre (0, 0) ccw
  arc A82 (6.7439, 0.4606) -> (6.4283, 0.1165) centre (6.767, 0.1227) ccw
  arc A83 (8.3875, 1.383) -> (8.4343, 1.533) centre (8.2677, 1.5027) ccw
  arc A84 (8.4343, 1.533) -> (8.3789, 1.8114) centre (0, 0) ccw
  arc A85 (8.3789, 1.8114) -> (8.2783, 1.9321) centre (8.2134, 1.7756) ccw
  arc A86 (5.9836, 2.3523) -> (6.4069, 2.1552) centre (6.2989, 2.4763) ccw
  arc A87 (5.9836, 2.3523) -> (5.8944, 2.5677) centre (0, 0) ccw
  arc A88 (6.0543, 3.0064) -> (5.8944, 2.5677) centre (6.205, 2.703) ccw
  arc A89 (7.2198, 4.4875) -> (7.2057, 4.6439) centre (7.0633, 4.5522) ccw
  arc A90 (7.2057, 4.6439) -> (7.0479, 4.88) centre (0, 0) ccw
  arc A91 (7.0479, 4.88) -> (6.9088, 4.953) centre (6.9087, 4.7836) ccw
  arc A92 (4.6279, 4.4631) -> (5.0944, 4.443) centre (4.8718, 4.6983) ccw
  arc A93 (4.6279, 4.4631) -> (4.4631, 4.6279) centre (0, 0) ccw
  arc A94 (4.443, 5.0944) -> (4.4631, 4.6279) centre (4.6983, 4.8718) ccw
  arc A95 (4.953, 6.9088) -> (4.88, 7.0479) centre (4.7836, 6.9087) ccw
  arc A96 (-1.8, 2.4) -> (1.8, 2.4) centre (0, 0) ccw construction
  arc A97 (-1.8, 2.4) -> (1.8, 2.4) centre (0, 0) ccw
  spline S0 degree 4 poles (4.4875, 7.2198) (4.4826, 7.2178) (4.45, 7.2043) (4.3869, 7.1776) (4.3159, 7.1453) (4.2063, 7.0938) (4.1109, 7.0449) (4.0089, 6.9904) (3.9133, 6.935) (3.8163, 6.8758) (3.7229, 6.8144) (3.6305, 6.7496) (3.5426, 6.6833) (3.4675, 6.6226) (3.4054, 6.5688) (3.355, 6.5228) (3.3144, 6.4839) (3.2747, 6.4441) (3.2361, 6.4032) (3.1925, 6.3543) (3.1539, 6.3073) (3.1216, 6.2645) (3.0966, 6.2276) (3.0838, 6.2074) (3.0764, 6.1947) (3.0728, 6.1879) (3.0715, 6.1854) knots 0 0 0 0 0 0.009879 0.064611 0.119344 0.174076 0.228808 0.283541 0.338273 0.393005 0.447738 0.50247 0.557202 0.60793 0.635296 0.662662 0.690028 0.717395 0.744761 0.772127 0.817627 0.835706 0.849154 0.858861 0.864237 0.864237 0.864237 0.864237 0.864237
  spline S1 degree 4 poles (2.2019, 6.5456) (2.2027, 6.5483) (2.205, 6.5557) (2.2087, 6.5699) (2.214, 6.5932) (2.2224, 6.637) (2.2298, 6.6901) (2.2357, 6.7506) (2.2395, 6.816) (2.2411, 6.8722) (2.2412, 6.9284) (2.24, 6.9846) (2.2369, 7.0528) (2.231, 7.1348) (2.2209, 7.2308) (2.2056, 7.3398) (2.186, 7.451) (2.1634, 7.5604) (2.1367, 7.6709) (2.1082, 7.7777) (2.0747, 7.8883) (2.0418, 7.9904) (2.0007, 8.1043) (1.9733, 8.1773) (1.9476, 8.2409) (1.9341, 8.2734) (1.9321, 8.2783) knots 0 0 0 0 0 0.005377 0.015084 0.028532 0.04661 0.092111 0.119476 0.146842 0.174209 0.201575 0.228941 0.256307 0.307035 0.361767 0.4165 0.471232 0.525964 0.580697 0.635429 0.690161 0.744894 0.799626 0.854358 0.864237 0.864237 0.864237 0.864237 0.864237
  spline S2 degree 4 poles (1.383, 8.3875) (1.3792, 8.3838) (1.3543, 8.3589) (1.3062, 8.31) (1.253, 8.253) (1.1714, 8.1635) (1.102, 8.0818) (1.0287, 7.9924) (0.9615, 7.9047) (0.8946, 7.8128) (0.8318, 7.7204) (0.7711, 7.6252) (0.7153, 7.5303) (0.6692, 7.4455) (0.6324, 7.372) (0.6035, 7.3102) (0.5808, 7.2587) (0.5594, 7.2067) (0.5394, 7.1542) (0.5178, 7.0923) (0.5001, 7.0342) (0.4867, 6.9822) (0.4776, 6.9386) (0.4736, 6.915) (0.4716, 6.9005) (0.4709, 6.8928) (0.4706, 6.89) knots 0 0 0 0 0 0.009879 0.064611 0.119344 0.174076 0.228808 0.283541 0.338273 0.393005 0.447738 0.50247 0.557202 0.60793 0.635296 0.662662 0.690028 0.717395 0.744761 0.772127 0.817627 0.835706 0.849154 0.858861 0.864237 0.864237 0.864237 0.864237 0.864237
  spline S3 degree 4 poles (-0.4706, 6.89) (-0.4709, 6.8928) (-0.4716, 6.9005) (-0.4736, 6.915) (-0.4776, 6.9386) (-0.4867, 6.9822) (-0.5001, 7.0342) (-0.5178, 7.0923) (-0.5394, 7.1542) (-0.5594, 7.2067) (-0.5808, 7.2587) (-0.6035, 7.3102) (-0.6324, 7.372) (-0.6692, 7.4455) (-0.7153, 7.5303) (-0.7711, 7.6252) (-0.8318, 7.7204) (-0.8946, 7.8128) (-0.9615, 7.9047) (-1.0287, 7.9924) (-1.102, 8.0818) (-1.1714, 8.1635) (-1.253, 8.253) (-1.3062, 8.31) (-1.3543, 8.3589) (-1.3792, 8.3838) (-1.383, 8.3875) knots 0 0 0 0 0 0.005377 0.015084 0.028532 0.04661 0.092111 0.119476 0.146842 0.174209 0.201575 0.228941 0.256307 0.307035 0.361767 0.4165 0.471232 0.525964 0.580697 0.635429 0.690161 0.744894 0.799626 0.854358 0.864237 0.864237 0.864237 0.864237 0.864237
  spline S4 degree 4 poles (-1.9321, 8.2783) (-1.9341, 8.2734) (-1.9476, 8.2409) (-1.9733, 8.1773) (-2.0007, 8.1043) (-2.0418, 7.9904) (-2.0747, 7.8883) (-2.1082, 7.7777) (-2.1367, 7.6709) (-2.1634, 7.5604) (-2.186, 7.451) (-2.2056, 7.3398) (-2.2209, 7.2308) (-2.231, 7.1348) (-2.2369, 7.0528) (-2.24, 6.9846) (-2.2412, 6.9284) (-2.2411, 6.8722) (-2.2395, 6.816) (-2.2357, 6.7506) (-2.2298, 6.6901) (-2.2224, 6.637) (-2.214, 6.5932) (-2.2087, 6.5699) (-2.205, 6.5557) (-2.2027, 6.5483) (-2.2019, 6.5456) knots 0 0 0 0 0 0.009879 0.064611 0.119344 0.174076 0.228808 0.283541 0.338273 0.393005 0.447738 0.50247 0.557202 0.60793 0.635296 0.662662 0.690028 0.717395 0.744761 0.772127 0.817627 0.835706 0.849154 0.858861 0.864237 0.864237 0.864237 0.864237 0.864237
  spline S5 degree 4 poles (-3.0715, 6.1854) (-3.0728, 6.1879) (-3.0764, 6.1947) (-3.0838, 6.2074) (-3.0966, 6.2276) (-3.1216, 6.2645) (-3.1539, 6.3073) (-3.1925, 6.3543) (-3.2361, 6.4032) (-3.2747, 6.4441) (-3.3144, 6.4839) (-3.355, 6.5228) (-3.4054, 6.5688) (-3.4675, 6.6226) (-3.5426, 6.6833) (-3.6305, 6.7496) (-3.7229, 6.8144) (-3.8163, 6.8758) (-3.9133, 6.935) (-4.0089, 6.9904) (-4.1109, 7.0449) (-4.2063, 7.0938) (-4.3159, 7.1453) (-4.3869, 7.1776) (-4.45, 7.2043) (-4.4826, 7.2178) (-4.4875, 7.2198) knots 0 0 0 0 0 0.005377 0.015084 0.028532 0.04661 0.092111 0.119476 0.146842 0.174209 0.201575 0.228941 0.256307 0.307035 0.361767 0.4165 0.471232 0.525964 0.580697 0.635429 0.690161 0.744894 0.799626 0.854358 0.864237 0.864237 0.864237 0.864237 0.864237
  spline S6 degree 4 poles (-4.953, 6.9088) (-4.953, 6.9035) (-4.9529, 6.8683) (-4.9524, 6.7997) (-4.9498, 6.7218) (-4.9442, 6.6008) (-4.9355, 6.4939) (-4.9241, 6.3789) (-4.9096, 6.2693) (-4.8919, 6.1571) (-4.871, 6.0473) (-4.8465, 5.9371) (-4.8189, 5.8305) (-4.7915, 5.7379) (-4.7656, 5.6599) (-4.7424, 5.5958) (-4.722, 5.5434) (-4.7004, 5.4915) (-4.6774, 5.4402) (-4.6489, 5.3812) (-4.6203, 5.3275) (-4.5931, 5.2813) (-4.5686, 5.2441) (-4.5547, 5.2245) (-4.5459, 5.2129) (-4.541, 5.2069) (-4.5392, 5.2048) knots 0 0 0 0 0 0.009879 0.064611 0.119344 0.174076 0.228808 0.283541 0.338273 0.393005 0.447738 0.50247 0.557202 0.60793 0.635296 0.662662 0.690028 0.717395 0.744761 0.772127 0.817627 0.835706 0.849154 0.858861 0.864237 0.864237 0.864237 0.864237 0.864237
  spline S7 degree 4 poles (-5.2048, 4.5392) (-5.2069, 4.541) (-5.2129, 4.5459) (-5.2245, 4.5547) (-5.2441, 4.5686) (-5.2813, 4.5931) (-5.3275, 4.6203) (-5.3812, 4.6489) (-5.4402, 4.6774) (-5.4915, 4.7004) (-5.5434, 4.722) (-5.5958, 4.7424) (-5.6599, 4.7656) (-5.7379, 4.7915) (-5.8305, 4.8189) (-5.9371, 4.8465) (-6.0473, 4.871) (-6.1571, 4.8919) (-6.2693, 4.9096) (-6.3789, 4.9241) (-6.4939, 4.9355) (-6.6008, 4.9442) (-6.7218, 4.9498) (-6.7997, 4.9524) (-6.8683, 4.9529) (-6.9035, 4.953) (-6.9088, 4.953) knots 0 0 0 0 0 0.005377 0.015084 0.028532 0.04661 0.092111 0.119476 0.146842 0.174209 0.201575 0.228941 0.256307 0.307035 0.361767 0.4165 0.471232 0.525964 0.580697 0.635429 0.690161 0.744894 0.799626 0.854358 0.864237 0.864237 0.864237 0.864237 0.864237
  spline S8 degree 4 poles (-7.2198, 4.4875) (-7.2178, 4.4826) (-7.2043, 4.45) (-7.1776, 4.3869) (-7.1453, 4.3159) (-7.0938, 4.2063) (-7.0449, 4.1109) (-6.9904, 4.0089) (-6.935, 3.9133) (-6.8758, 3.8163) (-6.8144, 3.7229) (-6.7496, 3.6305) (-6.6833, 3.5426) (-6.6226, 3.4675) (-6.5688, 3.4054) (-6.5228, 3.355) (-6.4839, 3.3144) (-6.4441, 3.2747) (-6.4032, 3.2361) (-6.3543, 3.1925) (-6.3073, 3.1539) (-6.2645, 3.1216) (-6.2276, 3.0966) (-6.2074, 3.0838) (-6.1947, 3.0764) (-6.1879, 3.0728) (-6.1854, 3.0715) knots 0 0 0 0 0 0.009879 0.064611 0.119344 0.174076 0.228808 0.283541 0.338273 0.393005 0.447738 0.50247 0.557202 0.60793 0.635296 0.662662 0.690028 0.717395 0.744761 0.772127 0.817627 0.835706 0.849154 0.858861 0.864237 0.864237 0.864237 0.864237 0.864237
  spline S9 degree 4 poles (-6.5456, 2.2019) (-6.5483, 2.2027) (-6.5557, 2.205) (-6.5699, 2.2087) (-6.5932, 2.214) (-6.637, 2.2224) (-6.6901, 2.2298) (-6.7506, 2.2357) (-6.816, 2.2395) (-6.8722, 2.2411) (-6.9284, 2.2412) (-6.9846, 2.24) (-7.0528, 2.2369) (-7.1348, 2.231) (-7.2308, 2.2209) (-7.3398, 2.2056) (-7.451, 2.186) (-7.5604, 2.1634) (-7.6709, 2.1367) (-7.7777, 2.1082) (-7.8883, 2.0747) (-7.9904, 2.0418) (-8.1043, 2.0007) (-8.1773, 1.9733) (-8.2409, 1.9476) (-8.2734, 1.9341) (-8.2783, 1.9321) knots 0 0 0 0 0 0.005377 0.015084 0.028532 0.04661 0.092111 0.119476 0.146842 0.174209 0.201575 0.228941 0.256307 0.307035 0.361767 0.4165 0.471232 0.525964 0.580697 0.635429 0.690161 0.744894 0.799626 0.854358 0.864237 0.864237 0.864237 0.864237 0.864237
  spline S10 degree 4 poles (-8.3875, 1.383) (-8.3838, 1.3792) (-8.3589, 1.3543) (-8.31, 1.3062) (-8.253, 1.253) (-8.1635, 1.1714) (-8.0818, 1.102) (-7.9924, 1.0287) (-7.9047, 0.9615) (-7.8128, 0.8946) (-7.7204, 0.8318) (-7.6252, 0.7711) (-7.5303, 0.7153) (-7.4455, 0.6692) (-7.372, 0.6324) (-7.3102, 0.6035) (-7.2587, 0.5808) (-7.2067, 0.5594) (-7.1542, 0.5394) (-7.0923, 0.5178) (-7.0342, 0.5001) (-6.9822, 0.4867) (-6.9386, 0.4776) (-6.915, 0.4736) (-6.9005, 0.4716) (-6.8928, 0.4709) (-6.89, 0.4706) knots 0 0 0 0 0 0.009879 0.064611 0.119344 0.174076 0.228808 0.283541 0.338273 0.393005 0.447738 0.50247 0.557202 0.60793 0.635296 0.662662 0.690028 0.717395 0.744761 0.772127 0.817627 0.835706 0.849154 0.858861 0.864237 0.864237 0.864237 0.864237 0.864237
  spline S11 degree 4 poles (-6.89, -0.4706) (-6.8928, -0.4709) (-6.9005, -0.4716) (-6.915, -0.4736) (-6.9386, -0.4776) (-6.9822, -0.4867) (-7.0342, -0.5001) (-7.0923, -0.5178) (-7.1542, -0.5394) (-7.2067, -0.5594) (-7.2587, -0.5808) (-7.3102, -0.6035) (-7.372, -0.6324) (-7.4455, -0.6692) (-7.5303, -0.7153) (-7.6252, -0.7711) (-7.7204, -0.8318) (-7.8128, -0.8946) (-7.9047, -0.9615) (-7.9924, -1.0287) (-8.0818, -1.102) (-8.1635, -1.1714) (-8.253, -1.253) (-8.31, -1.3062) (-8.3589, -1.3543) (-8.3838, -1.3792) (-8.3875, -1.383) knots 0 0 0 0 0 0.005377 0.015084 0.028532 0.04661 0.092111 0.119476 0.146842 0.174209 0.201575 0.228941 0.256307 0.307035 0.361767 0.4165 0.471232 0.525964 0.580697 0.635429 0.690161 0.744894 0.799626 0.854358 0.864237 0.864237 0.864237 0.864237 0.864237
  spline S12 degree 4 poles (-8.2783, -1.9321) (-8.2734, -1.9341) (-8.2409, -1.9476) (-8.1773, -1.9733) (-8.1043, -2.0007) (-7.9904, -2.0418) (-7.8883, -2.0747) (-7.7777, -2.1082) (-7.6709, -2.1367) (-7.5604, -2.1634) (-7.451, -2.186) (-7.3398, -2.2056) (-7.2308, -2.2209) (-7.1348, -2.231) (-7.0528, -2.2369) (-6.9846, -2.24) (-6.9284, -2.2412) (-6.8722, -2.2411) (-6.816, -2.2395) (-6.7506, -2.2357) (-6.6901, -2.2298) (-6.637, -2.2224) (-6.5932, -2.214) (-6.5699, -2.2087) (-6.5557, -2.205) (-6.5483, -2.2027) (-6.5456, -2.2019) knots 0 0 0 0 0 0.009879 0.064611 0.119344 0.174076 0.228808 0.283541 0.338273 0.393005 0.447738 0.50247 0.557202 0.60793 0.635296 0.662662 0.690028 0.717395 0.744761 0.772127 0.817627 0.835706 0.849154 0.858861 0.864237 0.864237 0.864237 0.864237 0.864237
  spline S13 degree 4 poles (-6.1854, -3.0715) (-6.1879, -3.0728) (-6.1947, -3.0764) (-6.2074, -3.0838) (-6.2276, -3.0966) (-6.2645, -3.1216) (-6.3073, -3.1539) (-6.3543, -3.1925) (-6.4032, -3.2361) (-6.4441, -3.2747) (-6.4839, -3.3144) (-6.5228, -3.355) (-6.5688, -3.4054) (-6.6226, -3.4675) (-6.6833, -3.5426) (-6.7496, -3.6305) (-6.8144, -3.7229) (-6.8758, -3.8163) (-6.935, -3.9133) (-6.9904, -4.0089) (-7.0449, -4.1109) (-7.0938, -4.2063) (-7.1453, -4.3159) (-7.1776, -4.3869) (-7.2043, -4.45) (-7.2178, -4.4826) (-7.2198, -4.4875) knots 0 0 0 0 0 0.005377 0.015084 0.028532 0.04661 0.092111 0.119476 0.146842 0.174209 0.201575 0.228941 0.256307 0.307035 0.361767 0.4165 0.471232 0.525964 0.580697 0.635429 0.690161 0.744894 0.799626 0.854358 0.864237 0.864237 0.864237 0.864237 0.864237
  spline S14 degree 4 poles (-6.9088, -4.953) (-6.9035, -4.953) (-6.8683, -4.9529) (-6.7997, -4.9524) (-6.7218, -4.9498) (-6.6008, -4.9442) (-6.4939, -4.9355) (-6.3789, -4.9241) (-6.2693, -4.9096) (-6.1571, -4.8919) (-6.0473, -4.871) (-5.9371, -4.8465) (-5.8305, -4.8189) (-5.7379, -4.7915) (-5.6599, -4.7656) (-5.5958, -4.7424) (-5.5434, -4.722) (-5.4915, -4.7004) (-5.4402, -4.6774) (-5.3812, -4.6489) (-5.3275, -4.6203) (-5.2813, -4.5931) (-5.2441, -4.5686) (-5.2245, -4.5547) (-5.2129, -4.5459) (-5.2069, -4.541) (-5.2048, -4.5392) knots 0 0 0 0 0 0.009879 0.064611 0.119344 0.174076 0.228808 0.283541 0.338273 0.393005 0.447738 0.50247 0.557202 0.60793 0.635296 0.662662 0.690028 0.717395 0.744761 0.772127 0.817627 0.835706 0.849154 0.858861 0.864237 0.864237 0.864237 0.864237 0.864237
  spline S15 degree 4 poles (-4.5392, -5.2048) (-4.541, -5.2069) (-4.5459, -5.2129) (-4.5547, -5.2245) (-4.5686, -5.2441) (-4.5931, -5.2813) (-4.6203, -5.3275) (-4.6489, -5.3812) (-4.6774, -5.4402) (-4.7004, -5.4915) (-4.722, -5.5434) (-4.7424, -5.5958) (-4.7656, -5.6599) (-4.7915, -5.7379) (-4.8189, -5.8305) (-4.8465, -5.9371) (-4.871, -6.0473) (-4.8919, -6.1571) (-4.9096, -6.2693) (-4.9241, -6.3789) (-4.9355, -6.4939) (-4.9442, -6.6008) (-4.9498, -6.7218) (-4.9524, -6.7997) (-4.9529, -6.8683) (-4.953, -6.9035) (-4.953, -6.9088) knots 0 0 0 0 0 0.005377 0.015084 0.028532 0.04661 0.092111 0.119476 0.146842 0.174209 0.201575 0.228941 0.256307 0.307035 0.361767 0.4165 0.471232 0.525964 0.580697 0.635429 0.690161 0.744894 0.799626 0.854358 0.864237 0.864237 0.864237 0.864237 0.864237
  spline S16 degree 4 poles (-4.4875, -7.2198) (-4.4826, -7.2178) (-4.45, -7.2043) (-4.3869, -7.1776) (-4.3159, -7.1453) (-4.2063, -7.0938) (-4.1109, -7.0449) (-4.0089, -6.9904) (-3.9133, -6.935) (-3.8163, -6.8758) (-3.7229, -6.8144) (-3.6305, -6.7496) (-3.5426, -6.6833) (-3.4675, -6.6226) (-3.4054, -6.5688) (-3.355, -6.5228) (-3.3144, -6.4839) (-3.2747, -6.4441) (-3.2361, -6.4032) (-3.1925, -6.3543) (-3.1539, -6.3073) (-3.1216, -6.2645) (-3.0966, -6.2276) (-3.0838, -6.2074) (-3.0764, -6.1947) (-3.0728, -6.1879) (-3.0715, -6.1854) knots 0 0 0 0 0 0.009879 0.064611 0.119344 0.174076 0.228808 0.283541 0.338273 0.393005 0.447738 0.50247 0.557202 0.60793 0.635296 0.662662 0.690028 0.717395 0.744761 0.772127 0.817627 0.835706 0.849154 0.858861 0.864237 0.864237 0.864237 0.864237 0.864237
  spline S17 degree 4 poles (-2.2019, -6.5456) (-2.2027, -6.5483) (-2.205, -6.5557) (-2.2087, -6.5699) (-2.214, -6.5932) (-2.2224, -6.637) (-2.2298, -6.6901) (-2.2357, -6.7506) (-2.2395, -6.816) (-2.2411, -6.8722) (-2.2412, -6.9284) (-2.24, -6.9846) (-2.2369, -7.0528) (-2.231, -7.1348) (-2.2209, -7.2308) (-2.2056, -7.3398) (-2.186, -7.451) (-2.1634, -7.5604) (-2.1367, -7.6709) (-2.1082, -7.7777) (-2.0747, -7.8883) (-2.0418, -7.9904) (-2.0007, -8.1043) (-1.9733, -8.1773) (-1.9476, -8.2409) (-1.9341, -8.2734) (-1.9321, -8.2783) knots 0 0 0 0 0 0.005377 0.015084 0.028532 0.04661 0.092111 0.119476 0.146842 0.174209 0.201575 0.228941 0.256307 0.307035 0.361767 0.4165 0.471232 0.525964 0.580697 0.635429 0.690161 0.744894 0.799626 0.854358 0.864237 0.864237 0.864237 0.864237 0.864237
  spline S18 degree 4 poles (-1.383, -8.3875) (-1.3792, -8.3838) (-1.3543, -8.3589) (-1.3062, -8.31) (-1.253, -8.253) (-1.1714, -8.1635) (-1.102, -8.0818) (-1.0287, -7.9924) (-0.9615, -7.9047) (-0.8946, -7.8128) (-0.8318, -7.7204) (-0.7711, -7.6252) (-0.7153, -7.5303) (-0.6692, -7.4455) (-0.6324, -7.372) (-0.6035, -7.3102) (-0.5808, -7.2587) (-0.5594, -7.2067) (-0.5394, -7.1542) (-0.5178, -7.0923) (-0.5001, -7.0342) (-0.4867, -6.9822) (-0.4776, -6.9386) (-0.4736, -6.915) (-0.4716, -6.9005) (-0.4709, -6.8928) (-0.4706, -6.89) knots 0 0 0 0 0 0.009879 0.064611 0.119344 0.174076 0.228808 0.283541 0.338273 0.393005 0.447738 0.50247 0.557202 0.60793 0.635296 0.662662 0.690028 0.717395 0.744761 0.772127 0.817627 0.835706 0.849154 0.858861 0.864237 0.864237 0.864237 0.864237 0.864237
  spline S19 degree 4 poles (0.4706, -6.89) (0.4709, -6.8928) (0.4716, -6.9005) (0.4736, -6.915) (0.4776, -6.9386) (0.4867, -6.9822) (0.5001, -7.0342) (0.5178, -7.0923) (0.5394, -7.1542) (0.5594, -7.2067) (0.5808, -7.2587) (0.6035, -7.3102) (0.6324, -7.372) (0.6692, -7.4455) (0.7153, -7.5303) (0.7711, -7.6252) (0.8318, -7.7204) (0.8946, -7.8128) (0.9615, -7.9047) (1.0287, -7.9924) (1.102, -8.0818) (1.1714, -8.1635) (1.253, -8.253) (1.3062, -8.31) (1.3543, -8.3589) (1.3792, -8.3838) (1.383, -8.3875) knots 0 0 0 0 0 0.005377 0.015084 0.028532 0.04661 0.092111 0.119476 0.146842 0.174209 0.201575 0.228941 0.256307 0.307035 0.361767 0.4165 0.471232 0.525964 0.580697 0.635429 0.690161 0.744894 0.799626 0.854358 0.864237 0.864237 0.864237 0.864237 0.864237
  spline S20 degree 4 poles (1.9321, -8.2783) (1.9341, -8.2734) (1.9476, -8.2409) (1.9733, -8.1773) (2.0007, -8.1043) (2.0418, -7.9904) (2.0747, -7.8883) (2.1082, -7.7777) (2.1367, -7.6709) (2.1634, -7.5604) (2.186, -7.451) (2.2056, -7.3398) (2.2209, -7.2308) (2.231, -7.1348) (2.2369, -7.0528) (2.24, -6.9846) (2.2412, -6.9284) (2.2411, -6.8722) (2.2395, -6.816) (2.2357, -6.7506) (2.2298, -6.6901) (2.2224, -6.637) (2.214, -6.5932) (2.2087, -6.5699) (2.205, -6.5557) (2.2027, -6.5483) (2.2019, -6.5456) knots 0 0 0 0 0 0.009879 0.064611 0.119344 0.174076 0.228808 0.283541 0.338273 0.393005 0.447738 0.50247 0.557202 0.60793 0.635296 0.662662 0.690028 0.717395 0.744761 0.772127 0.817627 0.835706 0.849154 0.858861 0.864237 0.864237 0.864237 0.864237 0.864237
  spline S21 degree 4 poles (3.0715, -6.1854) (3.0728, -6.1879) (3.0764, -6.1947) (3.0838, -6.2074) (3.0966, -6.2276) (3.1216, -6.2645) (3.1539, -6.3073) (3.1925, -6.3543) (3.2361, -6.4032) (3.2747, -6.4441) (3.3144, -6.4839) (3.355, -6.5228) (3.4054, -6.5688) (3.4675, -6.6226) (3.5426, -6.6833) (3.6305, -6.7496) (3.7229, -6.8144) (3.8163, -6.8758) (3.9133, -6.935) (4.0089, -6.9904) (4.1109, -7.0449) (4.2063, -7.0938) (4.3159, -7.1453) (4.3869, -7.1776) (4.45, -7.2043) (4.4826, -7.2178) (4.4875, -7.2198) knots 0 0 0 0 0 0.005377 0.015084 0.028532 0.04661 0.092111 0.119476 0.146842 0.174209 0.201575 0.228941 0.256307 0.307035 0.361767 0.4165 0.471232 0.525964 0.580697 0.635429 0.690161 0.744894 0.799626 0.854358 0.864237 0.864237 0.864237 0.864237 0.864237
  spline S22 degree 4 poles (4.953, -6.9088) (4.953, -6.9035) (4.9529, -6.8683) (4.9524, -6.7997) (4.9498, -6.7218) (4.9442, -6.6008) (4.9355, -6.4939) (4.9241, -6.3789) (4.9096, -6.2693) (4.8919, -6.1571) (4.871, -6.0473) (4.8465, -5.9371) (4.8189, -5.8305) (4.7915, -5.7379) (4.7656, -5.6599) (4.7424, -5.5958) (4.722, -5.5434) (4.7004, -5.4915) (4.6774, -5.4402) (4.6489, -5.3812) (4.6203, -5.3275) (4.5931, -5.2813) (4.5686, -5.2441) (4.5547, -5.2245) (4.5459, -5.2129) (4.541, -5.2069) (4.5392, -5.2048) knots 0 0 0 0 0 0.009879 0.064611 0.119344 0.174076 0.228808 0.283541 0.338273 0.393005 0.447738 0.50247 0.557202 0.60793 0.635296 0.662662 0.690028 0.717395 0.744761 0.772127 0.817627 0.835706 0.849154 0.858861 0.864237 0.864237 0.864237 0.864237 0.864237
  spline S23 degree 4 poles (5.2048, -4.5392) (5.2069, -4.541) (5.2129, -4.5459) (5.2245, -4.5547) (5.2441, -4.5686) (5.2813, -4.5931) (5.3275, -4.6203) (5.3812, -4.6489) (5.4402, -4.6774) (5.4915, -4.7004) (5.5434, -4.722) (5.5958, -4.7424) (5.6599, -4.7656) (5.7379, -4.7915) (5.8305, -4.8189) (5.9371, -4.8465) (6.0473, -4.871) (6.1571, -4.8919) (6.2693, -4.9096) (6.3789, -4.9241) (6.4939, -4.9355) (6.6008, -4.9442) (6.7218, -4.9498) (6.7997, -4.9524) (6.8683, -4.9529) (6.9035, -4.953) (6.9088, -4.953) knots 0 0 0 0 0 0.005377 0.015084 0.028532 0.04661 0.092111 0.119476 0.146842 0.174209 0.201575 0.228941 0.256307 0.307035 0.361767 0.4165 0.471232 0.525964 0.580697 0.635429 0.690161 0.744894 0.799626 0.854358 0.864237 0.864237 0.864237 0.864237 0.864237
  spline S24 degree 4 poles (7.2198, -4.4875) (7.2178, -4.4826) (7.2043, -4.45) (7.1776, -4.3869) (7.1453, -4.3159) (7.0938, -4.2063) (7.0449, -4.1109) (6.9904, -4.0089) (6.935, -3.9133) (6.8758, -3.8163) (6.8144, -3.7229) (6.7496, -3.6305) (6.6833, -3.5426) (6.6226, -3.4675) (6.5688, -3.4054) (6.5228, -3.355) (6.4839, -3.3144) (6.4441, -3.2747) (6.4032, -3.2361) (6.3543, -3.1925) (6.3073, -3.1539) (6.2645, -3.1216) (6.2276, -3.0966) (6.2074, -3.0838) (6.1947, -3.0764) (6.1879, -3.0728) (6.1854, -3.0715) knots 0 0 0 0 0 0.009879 0.064611 0.119344 0.174076 0.228808 0.283541 0.338273 0.393005 0.447738 0.50247 0.557202 0.60793 0.635296 0.662662 0.690028 0.717395 0.744761 0.772127 0.817627 0.835706 0.849154 0.858861 0.864237 0.864237 0.864237 0.864237 0.864237
  spline S25 degree 4 poles (6.5456, -2.2019) (6.5483, -2.2027) (6.5557, -2.205) (6.5699, -2.2087) (6.5932, -2.214) (6.637, -2.2224) (6.6901, -2.2298) (6.7506, -2.2357) (6.816, -2.2395) (6.8722, -2.2411) (6.9284, -2.2412) (6.9846, -2.24) (7.0528, -2.2369) (7.1348, -2.231) (7.2308, -2.2209) (7.3398, -2.2056) (7.451, -2.186) (7.5604, -2.1634) (7.6709, -2.1367) (7.7777, -2.1082) (7.8883, -2.0747) (7.9904, -2.0418) (8.1043, -2.0007) (8.1773, -1.9733) (8.2409, -1.9476) (8.2734, -1.9341) (8.2783, -1.9321) knots 0 0 0 0 0 0.005377 0.015084 0.028532 0.04661 0.092111 0.119476 0.146842 0.174209 0.201575 0.228941 0.256307 0.307035 0.361767 0.4165 0.471232 0.525964 0.580697 0.635429 0.690161 0.744894 0.799626 0.854358 0.864237 0.864237 0.864237 0.864237 0.864237
  spline S26 degree 4 poles (8.3875, -1.383) (8.3838, -1.3792) (8.3589, -1.3543) (8.31, -1.3062) (8.253, -1.253) (8.1635, -1.1714) (8.0818, -1.102) (7.9924, -1.0287) (7.9047, -0.9615) (7.8128, -0.8946) (7.7204, -0.8318) (7.6252, -0.7711) (7.5303, -0.7153) (7.4455, -0.6692) (7.372, -0.6324) (7.3102, -0.6035) (7.2587, -0.5808) (7.2067, -0.5594) (7.1542, -0.5394) (7.0923, -0.5178) (7.0342, -0.5001) (6.9822, -0.4867) (6.9386, -0.4776) (6.915, -0.4736) (6.9005, -0.4716) (6.8928, -0.4709) (6.89, -0.4706) knots 0 0 0 0 0 0.009879 0.064611 0.119344 0.174076 0.228808 0.283541 0.338273 0.393005 0.447738 0.50247 0.557202 0.60793 0.635296 0.662662 0.690028 0.717395 0.744761 0.772127 0.817627 0.835706 0.849154 0.858861 0.864237 0.864237 0.864237 0.864237 0.864237
  spline S27 degree 4 poles (6.89, 0.4706) (6.8928, 0.4709) (6.9005, 0.4716) (6.915, 0.4736) (6.9386, 0.4776) (6.9822, 0.4867) (7.0342, 0.5001) (7.0923, 0.5178) (7.1542, 0.5394) (7.2067, 0.5594) (7.2587, 0.5808) (7.3102, 0.6035) (7.372, 0.6324) (7.4455, 0.6692) (7.5303, 0.7153) (7.6252, 0.7711) (7.7204, 0.8318) (7.8128, 0.8946) (7.9047, 0.9615) (7.9924, 1.0287) (8.0818, 1.102) (8.1635, 1.1714) (8.253, 1.253) (8.31, 1.3062) (8.3589, 1.3543) (8.3838, 1.3792) (8.3875, 1.383) knots 0 0 0 0 0 0.005377 0.015084 0.028532 0.04661 0.092111 0.119476 0.146842 0.174209 0.201575 0.228941 0.256307 0.307035 0.361767 0.4165 0.471232 0.525964 0.580697 0.635429 0.690161 0.744894 0.799626 0.854358 0.864237 0.864237 0.864237 0.864237 0.864237
  spline S28 degree 4 poles (8.2783, 1.9321) (8.2734, 1.9341) (8.2409, 1.9476) (8.1773, 1.9733) (8.1043, 2.0007) (7.9904, 2.0418) (7.8883, 2.0747) (7.7777, 2.1082) (7.6709, 2.1367) (7.5604, 2.1634) (7.451, 2.186) (7.3398, 2.2056) (7.2308, 2.2209) (7.1348, 2.231) (7.0528, 2.2369) (6.9846, 2.24) (6.9284, 2.2412) (6.8722, 2.2411) (6.816, 2.2395) (6.7506, 2.2357) (6.6901, 2.2298) (6.637, 2.2224) (6.5932, 2.214) (6.5699, 2.2087) (6.5557, 2.205) (6.5483, 2.2027) (6.5456, 2.2019) knots 0 0 0 0 0 0.009879 0.064611 0.119344 0.174076 0.228808 0.283541 0.338273 0.393005 0.447738 0.50247 0.557202 0.60793 0.635296 0.662662 0.690028 0.717395 0.744761 0.772127 0.817627 0.835706 0.849154 0.858861 0.864237 0.864237 0.864237 0.864237 0.864237
  spline S29 degree 4 poles (6.1854, 3.0715) (6.1879, 3.0728) (6.1947, 3.0764) (6.2074, 3.0838) (6.2276, 3.0966) (6.2645, 3.1216) (6.3073, 3.1539) (6.3543, 3.1925) (6.4032, 3.2361) (6.4441, 3.2747) (6.4839, 3.3144) (6.5228, 3.355) (6.5688, 3.4054) (6.6226, 3.4675) (6.6833, 3.5426) (6.7496, 3.6305) (6.8144, 3.7229) (6.8758, 3.8163) (6.935, 3.9133) (6.9904, 4.0089) (7.0449, 4.1109) (7.0938, 4.2063) (7.1453, 4.3159) (7.1776, 4.3869) (7.2043, 4.45) (7.2178, 4.4826) (7.2198, 4.4875) knots 0 0 0 0 0 0.005377 0.015084 0.028532 0.04661 0.092111 0.119476 0.146842 0.174209 0.201575 0.228941 0.256307 0.307035 0.361767 0.4165 0.471232 0.525964 0.580697 0.635429 0.690161 0.744894 0.799626 0.854358 0.864237 0.864237 0.864237 0.864237 0.864237
  spline S30 degree 4 poles (6.9088, 4.953) (6.9035, 4.953) (6.8683, 4.9529) (6.7997, 4.9524) (6.7218, 4.9498) (6.6008, 4.9442) (6.4939, 4.9355) (6.3789, 4.9241) (6.2693, 4.9096) (6.1571, 4.8919) (6.0473, 4.871) (5.9371, 4.8465) (5.8305, 4.8189) (5.7379, 4.7915) (5.6599, 4.7656) (5.5958, 4.7424) (5.5434, 4.722) (5.4915, 4.7004) (5.4402, 4.6774) (5.3812, 4.6489) (5.3275, 4.6203) (5.2813, 4.5931) (5.2441, 4.5686) (5.2245, 4.5547) (5.2129, 4.5459) (5.2069, 4.541) (5.2048, 4.5392) knots 0 0 0 0 0 0.009879 0.064611 0.119344 0.174076 0.228808 0.283541 0.338273 0.393005 0.447738 0.50247 0.557202 0.60793 0.635296 0.662662 0.690028 0.717395 0.744761 0.772127 0.817627 0.835706 0.849154 0.858861 0.864237 0.864237 0.864237 0.864237 0.864237
  spline S31 degree 4 poles (4.5392, 5.2048) (4.541, 5.2069) (4.5459, 5.2129) (4.5547, 5.2245) (4.5686, 5.2441) (4.5931, 5.2813) (4.6203, 5.3275) (4.6489, 5.3812) (4.6774, 5.4402) (4.7004, 5.4915) (4.722, 5.5434) (4.7424, 5.5958) (4.7656, 5.6599) (4.7915, 5.7379) (4.8189, 5.8305) (4.8465, 5.9371) (4.871, 6.0473) (4.8919, 6.1571) (4.9096, 6.2693) (4.9241, 6.3789) (4.9355, 6.4939) (4.9442, 6.6008) (4.9498, 6.7218) (4.9524, 6.7997) (4.9529, 6.8683) (4.953, 6.9035) (4.953, 6.9088) knots 0 0 0 0 0 0.005377 0.015084 0.028532 0.04661 0.092111 0.119476 0.146842 0.174209 0.201575 0.228941 0.256307 0.307035 0.361767 0.4165 0.471232 0.525964 0.580697 0.635429 0.690161 0.744894 0.799626 0.854358 0.864237 0.864237 0.864237 0.864237 0.864237
extrude "Boss-Extrude2" add sketch "Sketch3" against normal up to surface (10.16 mm away)
sketch "Sketch4" plane through (0, 0, 0) normal (0, 0, 1) x (1, 0, 0)
  circle A0 centre (0, 0) radius 6.4294
